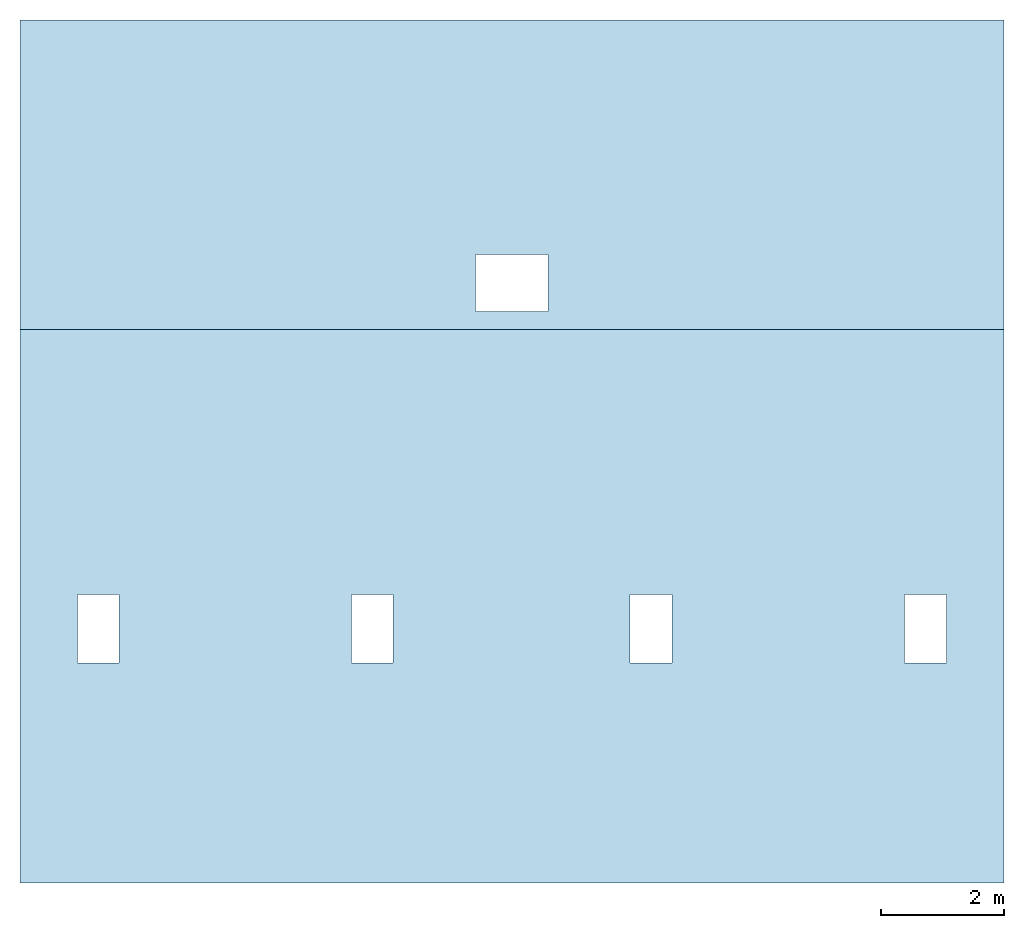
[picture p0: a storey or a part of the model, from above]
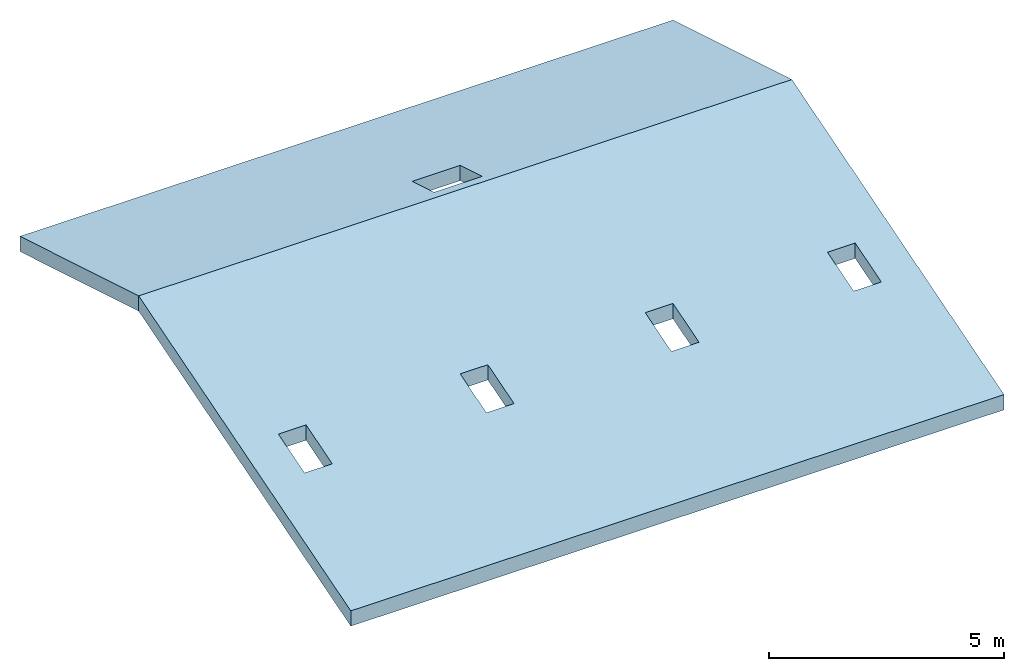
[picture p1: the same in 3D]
Properties of the parts of a building model (IFC2X3)

# File
Description: ArchiCAD 12.00 Release 1 generated IFC file., Build Number of the Ifc 2x3 interface: 63089 (04-06-2008)
File name: C:\Documents and Settings\Pruebas_CAD\Escritorio\escritorio\OBRA PLURIF 8 VIV\fichero ifc\Plurif_8_viviendas_sin_barandillas.ifc
Time: 2009-05-20T16:04:53
Author: Architect
Organization: Building Designer Office
Written by: PreProc - EDM 4.5.0033
Made in: Windows System
Authorization: The authorising person

# IfcSite, Por defecto Sitio
RefLatitude: 40, 25, 0; RefLongitude: -3, -43, 0

# IfcBuildingStorey (7)
In: Por defecto Edificio
Name | Elevation (m)
Planta Baja | 0
Primera | 4.2
Segunda | 7.2
Tercera | 10.2
Cuarta | 13.2
Bajo cubierta | 16.2
Cubierta | 19.7

# IfcDoor: P1 12 (25)
Type - OperationType: SINGLE_SWING_LEFT; ParameterTakesPrecedence: no; Sizeable: no
Type - IfcDoorLiningProperties - LiningDepth: 0.115 m; LiningThickness: 0.04 m
Type - IfcDoorPanelProperties - PanelDepth: 0.04 m; PanelOperation: SWINGING; PanelPosition: MIDDLE
OverallHeight: 2.1 m
Name | In | OverallWidth (m)
P07 | Planta Baja | 0.9
P20 | Primera | 0.7
P17 | Primera | 0.9
P21 | Primera | 0.9
P18 | Primera | 0.9
P15 | Primera | 0.9
P20 | Primera | 0.9
P20 | Segunda | 0.7
P18 | Segunda | 0.9
P17 | Segunda | 0.9
P15 | Segunda | 0.9
P21 | Segunda | 0.9
P20 | Segunda | 0.9
P17 | Tercera | 0.9
P20 | Tercera | 0.9
P21 | Tercera | 0.9
P15 | Tercera | 0.9
P18 | Tercera | 0.9
P20 | Tercera | 0.7
P21 | Cuarta | 0.9
P19 | Cuarta | 0.9
P18 | Cuarta | 0.9
P20 | Cuarta | 0.9
P20 | Cuarta | 0.7
P21 | Bajo cubierta | 0.7

# IfcDoor: P1 12 (35)
Type - OperationType: SINGLE_SWING_RIGHT; ParameterTakesPrecedence: no; Sizeable: no
Type - IfcDoorLiningProperties - LiningDepth: 0.115 m; LiningThickness: 0.04 m
Type - IfcDoorPanelProperties - PanelDepth: 0.04 m; PanelOperation: SWINGING; PanelPosition: MIDDLE
OverallHeight: 2.1 m
Name | In | OverallWidth (m)
P05 | Planta Baja | 0.9
P08 | Planta Baja | 0.9
P06 | Planta Baja | 0.9
6 x P09 | Planta Baja | 0.9
P20 | Primera | 0.7
P22 | Primera | 0.9
2 x P19 | Primera | 0.9
P16 | Primera | 0.9
P18 | Primera | 0.9
P20 | Segunda | 0.7
2 x P19 | Segunda | 0.9
P16 | Segunda | 0.9
P18 | Segunda | 0.9
P22 | Segunda | 0.9
P18 | Tercera | 0.9
2 x P19 | Tercera | 0.9
P22 | Tercera | 0.9
P20 | Tercera | 0.7
P16 | Tercera | 0.9
P23 | Cuarta | 0.9
2 x P22 | Cuarta | 0.9
P24 | Cuarta | 0.9
P25 | Cuarta | 0.9
P21 | Cuarta | 0.9
P21 | Cuarta | 0.7
P20 | Bajo cubierta | 0.7

# IfcDoor: P1 Entrada 12 (5)
Type - OperationType: SINGLE_SWING_LEFT; ParameterTakesPrecedence: no; Sizeable: no
Type - IfcDoorLiningProperties - LiningDepth: 0.075 m; LiningThickness: 0.05 m
Type - IfcDoorPanelProperties - PanelDepth: 0.044 m; PanelOperation: SWINGING; PanelPosition: MIDDLE
OverallHeight: 2.1 m
Name | In | OverallWidth (m)
P03 | Planta Baja | 1
P12 | Primera | 0.9
P12 | Segunda | 0.9
P12 | Tercera | 0.9
P15 | Cuarta | 0.9

# IfcDoor: P1 Entrada 12 (5)
Type - OperationType: SINGLE_SWING_RIGHT; ParameterTakesPrecedence: no; Sizeable: no
Type - IfcDoorLiningProperties - LiningDepth: 0.075 m; LiningThickness: 0.05 m
Type - IfcDoorPanelProperties - PanelDepth: 0.044 m; PanelOperation: SWINGING; PanelPosition: MIDDLE
OverallHeight: 2.1 m
Name | In | OverallWidth (m)
P04 | Planta Baja | 1
P14 | Primera | 0.9
P14 | Segunda | 0.9
P14 | Tercera | 0.9
P14 | Cuarta | 0.9

# IfcDoor: P1 Garaje 2 12, P10
In: Planta Baja
Type - OperationType: ROLLINGUP; ParameterTakesPrecedence: no; Sizeable: no
Type - IfcDoorLiningProperties - LiningDepth: 0.1 m; LiningThickness: 0.05 m
Type - IfcDoorPanelProperties - PanelDepth: 0.04 m; PanelOperation: ROLLINGUP; PanelPosition: MIDDLE
OverallHeight: 2.1 m; OverallWidth: 2.5 m

# IfcDoor: P2 12 (10)
Type - OperationType: DOUBLE_DOOR_SINGLE_SWING; ParameterTakesPrecedence: no; Sizeable: no
Type - IfcDoorLiningProperties - LiningDepth: 0.115 m; LiningThickness: 0.04 m
Type - IfcDoorPanelProperties - PanelOperation: SWINGING; PanelPosition: LEFT; PanelDepth: 0.04 m
OverallHeight: 2.1 m; OverallWidth: 1.5 m
Name | In
2 x P27 | Primera
2 x P27 | Segunda
2 x P27 | Tercera
2 x P28 | Cuarta
2 x P27 | Cuarta

# IfcDoor: P2 Corredera Ext 12 (8)
Type - OperationType: DOUBLE_DOOR_SLIDING; ParameterTakesPrecedence: no; Sizeable: no
Type - IfcDoorLiningProperties - LiningDepth: 0.00001 m; LiningThickness: 0.05 m
Type - IfcDoorPanelProperties - PanelOperation: SLIDING; PanelPosition: LEFT; PanelDepth: 0.04 m
OverallHeight: 2.1 m; OverallWidth: 1.2 m
Name | In
P29 | Primera
P30 | Primera
P29 | Segunda
P30 | Segunda
P29 | Tercera
P30 | Tercera
P30 | Cuarta
P31 | Cuarta

# IfcDoor: P3 Corredera 12 (4)
Type - OperationType: SLIDING_TO_LEFT; ParameterTakesPrecedence: no; Sizeable: no
Type - IfcDoorLiningProperties - LiningDepth: 0.15 m; LiningThickness: 0.03 m
Type - IfcDoorPanelProperties - PanelDepth: 0.05 m; PanelOperation: SLIDING; PanelPosition: LEFT
OverallHeight: 2.1 m; OverallWidth: 2.4 m
Name | In
P27 | Primera
P27 | Segunda
P27 | Tercera
P27 | Cuarta

# IfcDoor: P3 Corredera 12 (4)
Type - OperationType: SLIDING_TO_RIGHT; ParameterTakesPrecedence: no; Sizeable: no
Type - IfcDoorLiningProperties - LiningDepth: 0.15 m; LiningThickness: 0.03 m
Type - IfcDoorPanelProperties - PanelDepth: 0.05 m; PanelOperation: SLIDING; PanelPosition: RIGHT
OverallHeight: 2.1 m; OverallWidth: 2.4 m
Name | In
P26 | Primera
P26 | Segunda
P26 | Tercera
P26 | Cuarta

# IfcDoor: P4 Corredera 12 (6)
Type - OperationType: DOUBLE_DOOR_SLIDING; ParameterTakesPrecedence: no; Sizeable: no
Type - IfcDoorLiningProperties - LiningDepth: 0.1 m; LiningThickness: 0.032 m
Type - IfcDoorPanelProperties - PanelOperation: SLIDING; PanelPosition: LEFT; PanelDepth: 0.04 m
OverallHeight: 2.1 m; OverallWidth: 2.4 m
Name | In
2 x P21 | Primera
2 x P21 | Segunda
2 x P21 | Tercera

# IfcSlab (27)
Name | In | PredefinedType | Material
Forj-001 | Planta Baja | FLOOR | Hormigón en masa 0.5 m
2 x Forj-003 | Primera | FLOOR | Sólido + Punto&Línea 0.2 m
Forj-003 | Primera | FLOOR | Hormigón armado 0.3 m
Forj-002 | Primera | FLOOR | Sólido + Punto&Línea 0.3 m
Forj-003 | Primera | FLOOR | Escayola 0.3 m
Forj-003 | Segunda | FLOOR | Hormigón armado 0.3 m
3 x Forj-003 | Segunda | FLOOR | Sólido + Punto&Línea 0.2 m
Forj-004 | Segunda | FLOOR | Sólido + Punto&Línea 0.2 m
Forj-004 | Tercera | FLOOR | Sólido + Punto&Línea 0.2 m
Forj-003 | Tercera | FLOOR | Hormigón armado 0.3 m
3 x Forj-003 | Tercera | FLOOR | Sólido + Punto&Línea 0.2 m
Forj-004 | Cuarta | FLOOR | Sólido + Punto&Línea 0.2 m
3 x Forj-003 | Cuarta | FLOOR | Sólido + Punto&Línea 0.2 m
Forj-003 | Cuarta | FLOOR | Hormigón armado 0.3 m
Forj-003 | Cuarta | FLOOR | Escayola 0.3 m
Forj-004 | Cuarta | FLOOR | Escayola 0.3 m
Forj-002 | Bajo cubierta | FLOOR | Sólido + Punto&Línea 0.3 m
Forj-003 | Bajo cubierta | FLOOR | Hormigón armado 0.3 m
Cub-003 | Cubierta | ROOF | Grava 0.03 m, Primer Plano 0.005 m, Fibra de vidrio 0.12 m, Primer Plano 0.005 m, Hormigón armado 0.2 m, Escayola 0.02 m
Cub-002 | Cubierta | ROOF | Grava 0.03 m, Primer Plano 0.005 m, Fibra de vidrio 0.12 m, Primer Plano 0.005 m, Hormigón armado 0.2 m, Escayola 0.02 m

# IfcWallStandardCase: Doble 1:4 (12)
Type - ElementType: Doble 1:4
Material: Doble 1:4 0.25 m
Name | In
Muro-001 | Planta Baja
Muro-003 | Planta Baja
Muro-011 | Primera
Muro-017 | Primera
Muro-011 | Segunda
Muro-017 | Segunda
Muro-011 | Tercera
Muro-017 | Tercera
Muro-011 | Cuarta
Muro-017 | Cuarta
Muro-017 | Bajo cubierta
Muro-011 | Bajo cubierta

# IfcWallStandardCase: Ladrillo común (217)
Type - ElementType: Ladrillo común
Name | In | Material
Muro-002 | Planta Baja | Ladrillo común 0.25 m
2 x Muro-012 | Planta Baja | Ladrillo común 0.18 m
Muro-024 | Planta Baja | Ladrillo común 0.1 m
Muro-006 | Planta Baja | Ladrillo común 0.25 m
Muro-023 | Planta Baja | Ladrillo común 0.1 m
Muro-022 | Planta Baja | Ladrillo común 0.1 m
2 x Muro-008 | Planta Baja | Ladrillo común 0.25 m
2 x Muro-009 | Planta Baja | Ladrillo común 0.18 m
Muro-010 | Planta Baja | Ladrillo común 0.25 m
Muro-011 | Planta Baja | Ladrillo común 0.25 m
Muro-010 | Planta Baja | Ladrillo común 0.18 m
Muro-011 | Planta Baja | Ladrillo común 0.18 m
Muro-021 | Planta Baja | Ladrillo común 0.1 m
Muro-014 | Planta Baja | Ladrillo común 0.1 m
Muro-020 | Planta Baja | Ladrillo común 0.1 m
Muro-016 | Planta Baja | Ladrillo común 0.1 m
Muro-017 | Planta Baja | Ladrillo común 0.1 m
Muro-018 | Planta Baja | Ladrillo común 0.1 m
Muro-019 | Planta Baja | Ladrillo común 0.1 m
Muro-009 | Primera | Ladrillo común 0.18 m
2 x Muro-010 | Primera | Ladrillo común 0.18 m
Muro-011 | Primera | Ladrillo común 0.18 m
2 x Muro-012 | Primera | Ladrillo común 0.18 m
Muro-011 | Primera | Ladrillo común 0.25 m
Muro-012 | Primera | Ladrillo común 0.25 m
Muro-013 | Primera | Ladrillo común 0.25 m
Muro-014 | Primera | Ladrillo común 0.25 m
Muro-015 | Primera | Ladrillo común 0.25 m
Muro-016 | Primera | Ladrillo común 0.25 m
Muro-018 | Primera | Ladrillo común 0.18 m
2 x Muro-019 | Primera | Ladrillo común 0.1 m
4 x Muro-020 | Primera | Ladrillo común 0.1 m
2 x Muro-021 | Primera | Ladrillo común 0.1 m
2 x Muro-024 | Primera | Ladrillo común 0.1 m
2 x Muro-025 | Primera | Ladrillo común 0.1 m
2 x Muro-027 | Primera | Ladrillo común 0.1 m
4 x Muro-028 | Primera | Ladrillo común 0.1 m
2 x Muro-039 | Primera | Ladrillo común 0.1 m
2 x Muro-038 | Primera | Ladrillo común 0.1 m
2 x Muro-031 | Primera | Ladrillo común 0.1 m
3 x Muro-034 | Primera | Ladrillo común 0.1 m
2 x Muro-035 | Primera | Ladrillo común 0.1 m
2 x Muro-036 | Primera | Ladrillo común 0.1 m
2 x Muro-037 | Primera | Ladrillo común 0.1 m
Muro-023 | Primera | Ladrillo común 0.1 m
Muro-009 | Segunda | Ladrillo común 0.18 m
2 x Muro-010 | Segunda | Ladrillo común 0.18 m
Muro-011 | Segunda | Ladrillo común 0.18 m
2 x Muro-012 | Segunda | Ladrillo común 0.18 m
Muro-011 | Segunda | Ladrillo común 0.25 m
4 x Muro-028 | Segunda | Ladrillo común 0.1 m
2 x Muro-019 | Segunda | Ladrillo común 0.1 m
Muro-018 | Segunda | Ladrillo común 0.18 m
Muro-012 | Segunda | Ladrillo común 0.25 m
4 x Muro-020 | Segunda | Ladrillo común 0.1 m
2 x Muro-035 | Segunda | Ladrillo común 0.1 m
2 x Muro-036 | Segunda | Ladrillo común 0.1 m
2 x Muro-037 | Segunda | Ladrillo común 0.1 m
Muro-013 | Segunda | Ladrillo común 0.25 m
2 x Muro-039 | Segunda | Ladrillo común 0.1 m
Muro-014 | Segunda | Ladrillo común 0.25 m
Muro-015 | Segunda | Ladrillo común 0.25 m
Muro-016 | Segunda | Ladrillo común 0.25 m
3 x Muro-034 | Segunda | Ladrillo común 0.1 m
2 x Muro-021 | Segunda | Ladrillo común 0.1 m
2 x Muro-024 | Segunda | Ladrillo común 0.1 m
2 x Muro-025 | Segunda | Ladrillo común 0.1 m
2 x Muro-027 | Segunda | Ladrillo común 0.1 m
2 x Muro-038 | Segunda | Ladrillo común 0.1 m
2 x Muro-031 | Segunda | Ladrillo común 0.1 m
Muro-023 | Segunda | Ladrillo común 0.1 m
2 x Muro-027 | Tercera | Ladrillo común 0.1 m
4 x Muro-028 | Tercera | Ladrillo común 0.1 m
2 x Muro-024 | Tercera | Ladrillo común 0.1 m
2 x Muro-021 | Tercera | Ladrillo común 0.1 m
Muro-023 | Tercera | Ladrillo común 0.1 m
3 x Muro-034 | Tercera | Ladrillo común 0.1 m
2 x Muro-038 | Tercera | Ladrillo común 0.1 m
2 x Muro-039 | Tercera | Ladrillo común 0.1 m
Muro-015 | Tercera | Ladrillo común 0.25 m
Muro-013 | Tercera | Ladrillo común 0.25 m
4 x Muro-020 | Tercera | Ladrillo común 0.1 m
2 x Muro-037 | Tercera | Ladrillo común 0.1 m
2 x Muro-036 | Tercera | Ladrillo común 0.1 m
2 x Muro-035 | Tercera | Ladrillo común 0.1 m
Muro-012 | Tercera | Ladrillo común 0.25 m
Muro-016 | Tercera | Ladrillo común 0.25 m
Muro-014 | Tercera | Ladrillo común 0.25 m
2 x Muro-031 | Tercera | Ladrillo común 0.1 m
2 x Muro-025 | Tercera | Ladrillo común 0.1 m
Muro-018 | Tercera | Ladrillo común 0.18 m
2 x Muro-019 | Tercera | Ladrillo común 0.1 m
2 x Muro-012 | Tercera | Ladrillo común 0.18 m
Muro-011 | Tercera | Ladrillo común 0.25 m
Muro-011 | Tercera | Ladrillo común 0.18 m
2 x Muro-010 | Tercera | Ladrillo común 0.18 m
Muro-009 | Tercera | Ladrillo común 0.18 m
2 x Muro-026 | Cuarta | Ladrillo común 0.1 m
2 x Muro-025 | Cuarta | Ladrillo común 0.1 m
4 x Muro-024 | Cuarta | Ladrillo común 0.1 m
4 x Muro-023 | Cuarta | Ladrillo común 0.1 m
4 x Muro-022 | Cuarta | Ladrillo común 0.1 m
2 x Muro-021 | Cuarta | Ladrillo común 0.1 m
2 x Muro-020 | Cuarta | Ladrillo común 0.1 m
2 x Muro-019 | Cuarta | Ladrillo común 0.1 m
Muro-018 | Cuarta | Ladrillo común 0.25 m
Muro-017 | Cuarta | Ladrillo común 0.25 m
2 x Muro-015 | Cuarta | Ladrillo común 0.25 m
2 x Muro-014 | Cuarta | Ladrillo común 0.25 m
2 x Muro-013 | Cuarta | Ladrillo común 0.25 m
Muro-016 | Cuarta | Ladrillo común 0.25 m
Muro-018 | Cuarta | Ladrillo común 0.18 m
2 x Muro-012 | Cuarta | Ladrillo común 0.18 m
Muro-011 | Cuarta | Ladrillo común 0.25 m
Muro-011 | Cuarta | Ladrillo común 0.18 m
2 x Muro-010 | Cuarta | Ladrillo común 0.18 m
Muro-009 | Cuarta | Ladrillo común 0.18 m
2 x Muro-010 | Bajo cubierta | Ladrillo común 0.18 m
Muro-009 | Bajo cubierta | Ladrillo común 0.18 m
Muro-033 | Bajo cubierta | Ladrillo común 0.1 m
Muro-032 | Bajo cubierta | Ladrillo común 0.1 m
Muro-031 | Bajo cubierta | Ladrillo común 0.1 m
Muro-030 | Bajo cubierta | Ladrillo común 0.1 m
Muro-029 | Bajo cubierta | Ladrillo común 0.1 m
Muro-028 | Bajo cubierta | Ladrillo común 0.1 m
Muro-011 | Bajo cubierta | Ladrillo común 0.18 m
2 x Muro-012 | Bajo cubierta | Ladrillo común 0.18 m
Muro-011 | Bajo cubierta | Ladrillo común 0.25 m
Muro-018 | Bajo cubierta | Ladrillo común 0.25 m
Muro-018 | Bajo cubierta | Ladrillo común 0.18 m

# IfcWindow: V M Doble 12 (32)
Type - OperationType: DOUBLE_PANEL_HORIZONTAL; ParameterTakesPrecedence: no; Sizeable: no
Type - IfcWindowLiningProperties - LiningDepth: 0.05 m; LiningThickness: 0.05 m
Type - IfcWindowPanelProperties - PanelPosition: TOP
Name | In | OverallHeight (m) | OverallWidth (m)
V10 | Primera | 1.5 | 1.2
V14 | Primera | 1.5 | 1.5
V15 | Primera | 1.5 | 1.5
V07 | Primera | 1.5 | 1.8
V08 | Primera | 1.5 | 1.8
V17 | Primera | 1.5 | 1.5
V18 | Primera | 1.5 | 1.5
V09 | Segunda | 1.5 | 1.2
V12 | Segunda | 1.5 | 1.5
V13 | Segunda | 1.5 | 1.5
V05 | Segunda | 1.5 | 1.8
V06 | Segunda | 1.5 | 1.8
V10 | Segunda | 1.5 | 1.5
V11 | Segunda | 1.5 | 1.5
V08 | Tercera | 1.5 | 1.5
V09 | Tercera | 1.5 | 1.5
V06 | Tercera | 1.5 | 1.5
V07 | Tercera | 1.5 | 1.5
V03 | Tercera | 1.5 | 1.8
V04 | Tercera | 1.5 | 1.8
V08 | Tercera | 1.5 | 1.2
V06 | Cuarta | 1.5 | 1.5
V01 | Cuarta | 1.5 | 1.5
V02 | Cuarta | 1.5 | 1.5
V03 | Cuarta | 1.5 | 1.8
V04 | Cuarta | 1.5 | 1.8
V05 | Cuarta | 1.5 | 1.5
V07 | Cuarta | 1.5 | 1.2
V05 | Bajo cubierta | 1 | 1.5
V06 | Bajo cubierta | 1 | 1.5
V07 | Bajo cubierta | 1 | 1.5
V08 | Bajo cubierta | 1 | 1.5
